One B-rep face of a CAD part: STEP entity #873.
In plain terms, the planar face has unit normal (0, 0, 1).
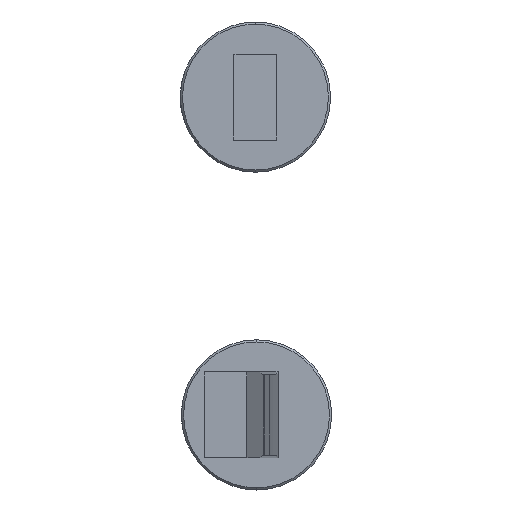
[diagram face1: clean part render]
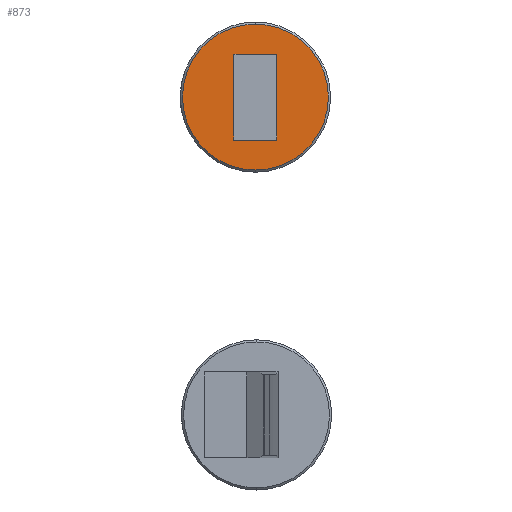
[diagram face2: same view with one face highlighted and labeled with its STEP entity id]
Its self-contained STEP definition (entity closure, numbers rounded to 3 decimals):
#50 = CARTESIAN_POINT ( 'NONE',  ( -6.8, 0., 8. ) ) ;
#57 = CARTESIAN_POINT ( 'NONE',  ( -4., -2., 8. ) ) ;
#379 = CARTESIAN_POINT ( 'NONE',  ( 0., 0., 8. ) ) ;
#382 = DIRECTION ( 'NONE',  ( 0., 0., -1. ) ) ;
#393 = DIRECTION ( 'NONE',  ( -1., 0., 0. ) ) ;
#437 = CARTESIAN_POINT ( 'NONE',  ( 4., 2., 8. ) ) ;
#816 = CIRCLE ( 'NONE', #819, 6.8 ) ;
#819 = AXIS2_PLACEMENT_3D ( 'NONE', #379, #382, #393 ) ;
#873 = ADVANCED_FACE ( 'NONE', ( #2081, #2071 ), #2065, .T. ) ;
#954 = EDGE_CURVE ( 'NONE', #1817, #1036, #816, .T. ) ;
#976 = VERTEX_POINT ( 'NONE', #437 ) ;
#1024 = VERTEX_POINT ( 'NONE', #2429 ) ;
#1026 = VERTEX_POINT ( 'NONE', #2471 ) ;
#1036 = VERTEX_POINT ( 'NONE', #2431 ) ;
#1275 = EDGE_LOOP ( 'NONE', ( #1486, #1487, #1898, #1798 ) ) ;
#1486 = ORIENTED_EDGE ( 'NONE', *, *, #1637, .T. ) ;
#1487 = ORIENTED_EDGE ( 'NONE', *, *, #1603, .T. ) ;
#1603 = EDGE_CURVE ( 'NONE', #976, #1026, #2441, .T. ) ;
#1607 = EDGE_CURVE ( 'NONE', #1835, #1024, #2499, .T. ) ;
#1627 = EDGE_CURVE ( 'NONE', #1036, #1817, #2318, .T. ) ;
#1637 = EDGE_CURVE ( 'NONE', #1024, #976, #2605, .T. ) ;
#1639 = EDGE_CURVE ( 'NONE', #1026, #1835, #2625, .T. ) ;
#1674 = AXIS2_PLACEMENT_3D ( 'NONE', #2066, #2082, #2056 ) ;
#1752 = EDGE_LOOP ( 'NONE', ( #1829, #1843 ) ) ;
#1798 = ORIENTED_EDGE ( 'NONE', *, *, #1607, .T. ) ;
#1817 = VERTEX_POINT ( 'NONE', #50 ) ;
#1829 = ORIENTED_EDGE ( 'NONE', *, *, #954, .F. ) ;
#1835 = VERTEX_POINT ( 'NONE', #57 ) ;
#1843 = ORIENTED_EDGE ( 'NONE', *, *, #1627, .F. ) ;
#1898 = ORIENTED_EDGE ( 'NONE', *, *, #1639, .T. ) ;
#2056 = DIRECTION ( 'NONE',  ( 1., 0., 0. ) ) ;
#2065 = PLANE ( 'NONE',  #1674 ) ;
#2066 = CARTESIAN_POINT ( 'NONE',  ( 0., 0., 8. ) ) ;
#2071 = FACE_OUTER_BOUND ( 'NONE', #1752, .T. ) ;
#2081 = FACE_BOUND ( 'NONE', #1275, .T. ) ;
#2082 = DIRECTION ( 'NONE',  ( 0., 0., 1. ) ) ;
#2310 = VECTOR ( 'NONE', #2607, 1000. ) ;
#2318 = CIRCLE ( 'NONE', #2359, 6.8 ) ;
#2330 = VECTOR ( 'NONE', #2633, 1000. ) ;
#2337 = VECTOR ( 'NONE', #2435, 1000. ) ;
#2343 = VECTOR ( 'NONE', #2508, 1000. ) ;
#2359 = AXIS2_PLACEMENT_3D ( 'NONE', #2615, #2584, #2590 ) ;
#2429 = CARTESIAN_POINT ( 'NONE',  ( -4., 2., 8. ) ) ;
#2431 = CARTESIAN_POINT ( 'NONE',  ( 6.8, 0., 8. ) ) ;
#2435 = DIRECTION ( 'NONE',  ( 0., -1., 0. ) ) ;
#2441 = LINE ( 'NONE', #2449, #2337 ) ;
#2449 = CARTESIAN_POINT ( 'NONE',  ( 4., 0., 8. ) ) ;
#2471 = CARTESIAN_POINT ( 'NONE',  ( 4., -2., 8. ) ) ;
#2481 = CARTESIAN_POINT ( 'NONE',  ( -4., 0., 8. ) ) ;
#2499 = LINE ( 'NONE', #2481, #2343 ) ;
#2508 = DIRECTION ( 'NONE',  ( 0., 1., 0. ) ) ;
#2584 = DIRECTION ( 'NONE',  ( 0., 0., -1. ) ) ;
#2590 = DIRECTION ( 'NONE',  ( -1., 0., 0. ) ) ;
#2604 = CARTESIAN_POINT ( 'NONE',  ( 0., 2., 8. ) ) ;
#2605 = LINE ( 'NONE', #2604, #2310 ) ;
#2607 = DIRECTION ( 'NONE',  ( 1., 0., 0. ) ) ;
#2615 = CARTESIAN_POINT ( 'NONE',  ( 0., 0., 8. ) ) ;
#2625 = LINE ( 'NONE', #2627, #2330 ) ;
#2627 = CARTESIAN_POINT ( 'NONE',  ( 0., -2., 8. ) ) ;
#2633 = DIRECTION ( 'NONE',  ( -1., 0., 0. ) ) ;
